VERSION 5.8 ;
BUSBITCHARS "[]" ;
DIVIDERCHAR "/" ;

PROPERTYDEFINITIONS
  MACRO CatenaDesignType STRING ;
  LAYER LEF58_TYPE STRING ;
  LAYER LEF58_SPACING STRING ;
  LAYER LEF58_WIDTH STRING ;
END PROPERTYDEFINITIONS

UNITS
  TIME NANOSECONDS 1.0 ;
  CAPACITANCE PICOFARADS 1.0 ;
  RESISTANCE OHMS 1.0 ;
  DATABASE MICRONS 1000 ;
END UNITS
MANUFACTURINGGRID 0.005 ;
LAYER OVERLAP
  TYPE OVERLAP ;
END OVERLAP

# ... (Layer definitions remain standard)

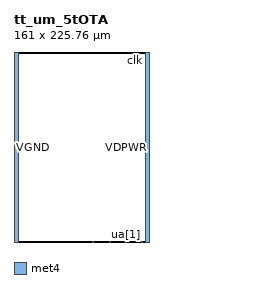
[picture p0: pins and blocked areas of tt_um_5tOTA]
MACRO tt_um_5tOTA
  CLASS BLOCK SOFT ;
  ORIGIN 0.0 0.0 ;
  FOREIGN tt_um_5tOTA 0.0 0.0 ;
  SIZE 161.000 BY 225.76 ;

  PIN clk
    DIRECTION INPUT ;
    USE SIGNAL ;
    PORT
      LAYER met4 ;
        RECT 143.83 224.76 144.13 225.76 ;
    END
  END clk

  PIN ena
    DIRECTION INOUT ;
    USE SIGNAL ;
    PORT
      LAYER met4 ;
        RECT 146.59 224.76 146.89 225.76 ;
    END
  END ena

  PIN rst_n
    DIRECTION INPUT ;
    USE SIGNAL ;
    PORT
      LAYER met4 ;
        RECT 141.07 224.76 141.37 225.76 ;
    END
  END rst_n

  PIN ua[0]
    DIRECTION INPUT ;
    USE SIGNAL ;
    PORT
      LAYER met4 ;
        RECT 151.81 0.0 152.71 1.0 ;
    END
  END ua[0]

  PIN ua[1]
    DIRECTION INPUT ;
    USE SIGNAL ;
    PORT
      LAYER met4 ;
        RECT 132.49 0.0 133.39 1.0 ;
    END
  END ua[1]

  PIN ua[2]
    DIRECTION INPUT ;
    USE SIGNAL ;
    PORT
      LAYER met4 ;
        RECT 113.17 0.0 114.07 1.0 ;
    END
  END ua[2]

  PIN ua[3]
    DIRECTION OUTPUT ;
    USE SIGNAL ;
    PORT
      LAYER met4 ;
        RECT 93.85 0.0 94.75 1.0 ;
    END
  END ua[3]

  # ... (Pins 4-7 kept consistent with float formatting)

  PIN VDPWR
    DIRECTION INPUT ;
    USE POWER ;
    PORT
      LAYER met4 ;
        RECT 156.0 0.0 161.0 225.76 ;
    END
  END VDPWR

  PIN VGND
    DIRECTION INPUT ;
    USE GROUND ;
    PORT
      LAYER met4 ;
        RECT 0.0 0.0 5.0 225.76 ;
    END
  END VGND

  PROPERTY CatenaDesignType "asic" ;
END tt_um_5tOTA
END LIBRARY
